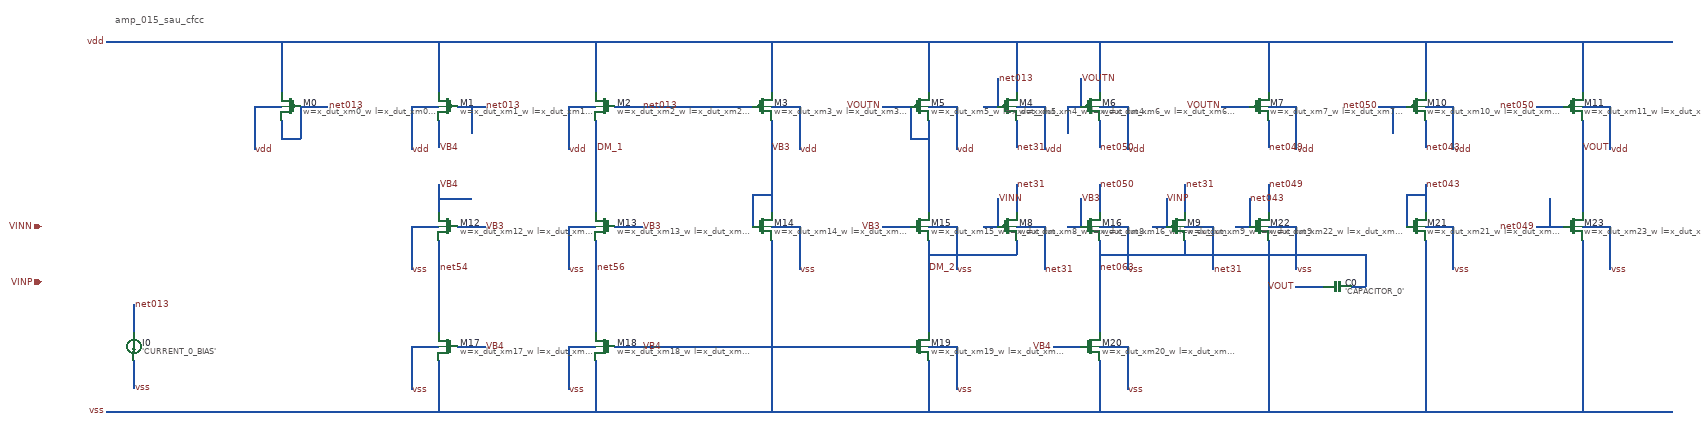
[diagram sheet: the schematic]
v {xschem version=3.4.6 file_version=1.2}
G {}
K {}
V {}
S {}
E {}
T {amp_015_sau_cfcc} -1740 -200 0 0 0.4 0.4 {}
C {devices/capa_np.sym} 905 390 1 0 {name=C0 value='CAPACITOR_0'}
C {devices/isource_np.sym} -1700 520 0 0 {name=I0 value='CURRENT_0_BIAS'}
C {devices/sg13_lv_pmos_np.sym} -1360 0 0 1 {name=M0 model=sg13_lv_pmos spiceprefix=X w=x_dut_xm0_w l=x_dut_xm0_l m=x_dut_xm0_m}
C {devices/sg13_lv_pmos_np.sym} -1020 0 0 1 {name=M1 model=sg13_lv_pmos spiceprefix=X w=x_dut_xm1_w l=x_dut_xm1_l m=x_dut_xm1_m}
C {devices/sg13_lv_pmos_np.sym} 1075 0 0 0 {name=M10 model=sg13_lv_pmos spiceprefix=X w=x_dut_xm10_w l=x_dut_xm10_l m=x_dut_xm10_m}
C {devices/sg13_lv_pmos_np.sym} 1415 0 0 0 {name=M11 model=sg13_lv_pmos spiceprefix=X w=x_dut_xm11_w l=x_dut_xm11_l m=x_dut_xm11_m}
C {devices/sg13_lv_nmos_np.sym} -1020 260 0 1 {name=M12 model=sg13_lv_nmos spiceprefix=X w=x_dut_xm12_w l=x_dut_xm12_l m=x_dut_xm12_m}
C {devices/sg13_lv_nmos_np.sym} -680 260 0 1 {name=M13 model=sg13_lv_nmos spiceprefix=X w=x_dut_xm13_w l=x_dut_xm13_l m=x_dut_xm13_m}
C {devices/sg13_lv_nmos_np.sym} -340 260 0 0 {name=M14 model=sg13_lv_nmos spiceprefix=X w=x_dut_xm14_w l=x_dut_xm14_l m=x_dut_xm14_m}
C {devices/sg13_lv_nmos_np.sym} 0 260 0 0 {name=M15 model=sg13_lv_nmos spiceprefix=X w=x_dut_xm15_w l=x_dut_xm15_l m=x_dut_xm15_m}
C {devices/sg13_lv_nmos_np.sym} 370 260 0 0 {name=M16 model=sg13_lv_nmos spiceprefix=X w=x_dut_xm16_w l=x_dut_xm16_l m=x_dut_xm16_m}
C {devices/sg13_lv_nmos_np.sym} -1020 520 0 1 {name=M17 model=sg13_lv_nmos spiceprefix=X w=x_dut_xm17_w l=x_dut_xm17_l m=x_dut_xm17_m}
C {devices/sg13_lv_nmos_np.sym} -680 520 0 1 {name=M18 model=sg13_lv_nmos spiceprefix=X w=x_dut_xm18_w l=x_dut_xm18_l m=x_dut_xm18_m}
C {devices/sg13_lv_nmos_np.sym} 0 520 0 0 {name=M19 model=sg13_lv_nmos spiceprefix=X w=x_dut_xm19_w l=x_dut_xm19_l m=x_dut_xm19_m}
C {devices/sg13_lv_pmos_np.sym} -680 0 0 1 {name=M2 model=sg13_lv_pmos spiceprefix=X w=x_dut_xm2_w l=x_dut_xm2_l m=x_dut_xm2_m}
C {devices/sg13_lv_nmos_np.sym} 370 520 0 0 {name=M20 model=sg13_lv_nmos spiceprefix=X w=x_dut_xm20_w l=x_dut_xm20_l m=x_dut_xm20_m}
C {devices/sg13_lv_nmos_np.sym} 1075 260 0 0 {name=M21 model=sg13_lv_nmos spiceprefix=X w=x_dut_xm21_w l=x_dut_xm21_l m=x_dut_xm21_m}
C {devices/sg13_lv_nmos_np.sym} 735 260 0 0 {name=M22 model=sg13_lv_nmos spiceprefix=X w=x_dut_xm22_w l=x_dut_xm22_l m=x_dut_xm22_m}
C {devices/sg13_lv_nmos_np.sym} 1415 260 0 0 {name=M23 model=sg13_lv_nmos spiceprefix=X w=x_dut_xm23_w l=x_dut_xm23_l m=x_dut_xm23_m}
C {devices/sg13_lv_pmos_np.sym} -340 0 0 0 {name=M3 model=sg13_lv_pmos spiceprefix=X w=x_dut_xm3_w l=x_dut_xm3_l m=x_dut_xm3_m}
C {devices/sg13_lv_pmos_np.sym} 190 0 0 0 {name=M4 model=sg13_lv_pmos spiceprefix=X w=x_dut_xm4_w l=x_dut_xm4_l m=x_dut_xm4_m}
C {devices/sg13_lv_pmos_np.sym} 0 0 0 0 {name=M5 model=sg13_lv_pmos spiceprefix=X w=x_dut_xm5_w l=x_dut_xm5_l m=x_dut_xm5_m}
C {devices/sg13_lv_pmos_np.sym} 370 0 0 0 {name=M6 model=sg13_lv_pmos spiceprefix=X w=x_dut_xm6_w l=x_dut_xm6_l m=x_dut_xm6_m}
C {devices/sg13_lv_pmos_np.sym} 735 0 0 0 {name=M7 model=sg13_lv_pmos spiceprefix=X w=x_dut_xm7_w l=x_dut_xm7_l m=x_dut_xm7_m}
C {devices/sg13_lv_pmos_np.sym} 190 260 0 0 {name=M8 model=sg13_lv_pmos spiceprefix=X w=x_dut_xm8_w l=x_dut_xm8_l m=x_dut_xm8_m}
C {devices/sg13_lv_pmos_np.sym} 555 260 0 0 {name=M9 model=sg13_lv_pmos spiceprefix=X w=x_dut_xm9_w l=x_dut_xm9_l m=x_dut_xm9_m}
N -1700 430 -1700 490 {}
N -1700 550 -1700 610 {}
N -1440 0 -1440 94 {}
N -1380 -140 -1380 -30 {}
N -1380 30 -1380 70 {}
N -1340 0 -1340 70 {}
N -1100 0 -1100 94 {}
N -1100 260 -1100 354 {}
N -1100 520 -1100 614 {}
N -1040 -140 -1040 -30 {}
N -1040 30 -1040 90 {}
N -1040 170 -1040 230 {}
N -1040 290 -1040 490 {}
N -1040 550 -1040 660 {}
N -970 0 -970 60 {}
N -760 0 -760 94 {}
N -760 260 -760 354 {}
N -760 520 -760 614 {}
N -700 -140 -700 -30 {}
N -700 30 -700 230 {}
N -700 290 -700 490 {}
N -700 550 -700 660 {}
N -360 190 -360 260 {}
N -320 -140 -320 -30 {}
N -320 30 -320 230 {}
N -320 290 -320 660 {}
N -260 0 -260 94 {}
N -260 260 -260 354 {}
N -20 0 -20 70 {}
N 20 -140 20 -30 {}
N 20 30 20 230 {}
N 20 290 20 490 {}
N 20 550 20 660 {}
N 80 0 80 94 {}
N 80 260 80 354 {}
N 80 520 80 614 {}
N 170 -60 170 0 {}
N 170 200 170 260 {}
N 210 -140 210 -30 {}
N 210 30 210 90 {}
N 210 170 210 230 {}
N 210 290 210 320 {}
N 270 0 270 94 {}
N 270 260 270 354 {}
N 320 0 320 60 {}
N 350 -60 350 0 {}
N 350 200 350 260 {}
N 390 -140 390 -30 {}
N 390 30 390 90 {}
N 390 170 390 230 {}
N 390 290 390 490 {}
N 390 550 390 660 {}
N 450 0 450 94 {}
N 450 260 450 354 {}
N 450 520 450 614 {}
N 535 200 535 260 {}
N 575 170 575 230 {}
N 575 290 575 320 {}
N 635 260 635 354 {}
N 715 200 715 260 {}
N 755 -140 755 -30 {}
N 755 30 755 90 {}
N 755 170 755 230 {}
N 755 290 755 660 {}
N 815 0 815 94 {}
N 815 260 815 354 {}
N 965 320 965 390 {}
N 1025 0 1025 60 {}
N 1055 190 1055 260 {}
N 1095 -140 1095 -30 {}
N 1095 30 1095 90 {}
N 1095 170 1095 230 {}
N 1095 290 1095 660 {}
N 1155 0 1155 94 {}
N 1155 260 1155 354 {}
N 1365 200 1365 260 {}
N 1435 -140 1435 -30 {}
N 1435 30 1435 230 {}
N 1435 290 1435 660 {}
N 1495 0 1495 94 {}
N 1495 260 1495 354 {}
N -1760 -140 1630 -140 {}
N -1440 0 -1380 0 {}
N -1340 0 -1280 0 {}
N -1100 0 -1040 0 {}
N -1000 0 -940 0 {}
N -760 0 -700 0 {}
N -660 0 -360 0 {}
N -320 0 -260 0 {}
N -80 0 -20 0 {}
N 20 0 80 0 {}
N 140 0 170 0 {}
N 210 0 270 0 {}
N 320 0 350 0 {}
N 390 0 450 0 {}
N 655 0 715 0 {}
N 755 0 815 0 {}
N 995 0 1055 0 {}
N 1095 0 1155 0 {}
N 1335 0 1395 0 {}
N 1435 0 1495 0 {}
N -1380 70 -1340 70 {}
N -20 70 20 70 {}
N -360 190 -320 190 {}
N 1055 190 1095 190 {}
N -1040 200 -970 200 {}
N -1100 260 -1040 260 {}
N -1000 260 -940 260 {}
N -760 260 -700 260 {}
N -660 260 -600 260 {}
N -320 260 -260 260 {}
N -80 260 -20 260 {}
N 20 260 80 260 {}
N 140 260 170 260 {}
N 210 260 270 260 {}
N 320 260 350 260 {}
N 390 260 450 260 {}
N 505 260 535 260 {}
N 575 260 635 260 {}
N 685 260 715 260 {}
N 755 260 815 260 {}
N 1095 260 1155 260 {}
N 1335 260 1395 260 {}
N 1435 260 1495 260 {}
N 20 320 210 320 {}
N 390 320 965 320 {}
N 815 390 875 390 {}
N 935 390 965 390 {}
N -1100 520 -1040 520 {}
N -1000 520 -940 520 {}
N -760 520 -700 520 {}
N -660 520 -20 520 {}
N 20 520 80 520 {}
N 290 520 350 520 {}
N 390 520 450 520 {}
N -1760 660 1630 660 {}
C {devices/lab_wire.sym} -1760 -140 0 0 {name=l0 lab=vdd}
C {devices/lab_wire.sym} -1760 660 0 0 {name=l1 lab=vss}
C {devices/lab_wire.sym} -700 90 2 0 {name=l2 lab=DM_1}
C {devices/lab_wire.sym} 20 350 2 0 {name=l3 lab=DM_2}
C {devices/lab_wire.sym} -940 260 0 1 {name=l4 lab=VB3}
C {devices/lab_wire.sym} -600 260 0 1 {name=l5 lab=VB3}
C {devices/lab_wire.sym} -320 90 2 0 {name=l6 lab=VB3}
C {devices/lab_wire.sym} -80 260 0 0 {name=l7 lab=VB3}
C {devices/lab_wire.sym} 350 200 0 1 {name=l8 lab=VB3}
C {devices/lab_wire.sym} -1040 90 2 0 {name=l9 lab=VB4}
C {devices/lab_wire.sym} -1040 170 0 1 {name=l10 lab=VB4}
C {devices/lab_wire.sym} -940 520 0 1 {name=l11 lab=VB4}
C {devices/lab_wire.sym} -600 520 0 1 {name=l12 lab=VB4}
C {devices/lab_wire.sym} 290 520 0 0 {name=l13 lab=VB4}
C {devices/lab_wire.sym} 170 200 0 1 {name=l14 lab=VINN}
C {devices/lab_wire.sym} 535 200 0 1 {name=l15 lab=VINP}
C {devices/lab_wire.sym} 815 390 0 0 {name=l16 lab=VOUT}
C {devices/lab_wire.sym} 1435 90 2 0 {name=l17 lab=VOUT}
C {devices/lab_wire.sym} -80 0 0 0 {name=l18 lab=VOUTN}
C {devices/lab_wire.sym} 350 -60 0 1 {name=l19 lab=VOUTN}
C {devices/lab_wire.sym} 655 0 0 0 {name=l20 lab=VOUTN}
C {devices/lab_wire.sym} -1280 0 0 1 {name=l21 lab=net013}
C {devices/lab_wire.sym} -940 0 0 1 {name=l22 lab=net013}
C {devices/lab_wire.sym} -600 0 0 1 {name=l23 lab=net013}
C {devices/lab_wire.sym} 170 -60 0 1 {name=l24 lab=net013}
C {devices/lab_wire.sym} 715 200 0 1 {name=l25 lab=net043}
C {devices/lab_wire.sym} 1095 170 0 1 {name=l26 lab=net043}
C {devices/lab_wire.sym} 1095 90 2 0 {name=l27 lab=net043}
C {devices/lab_wire.sym} 755 90 2 0 {name=l28 lab=net049}
C {devices/lab_wire.sym} 755 170 0 1 {name=l29 lab=net049}
C {devices/lab_wire.sym} 1335 260 0 0 {name=l30 lab=net049}
C {devices/lab_wire.sym} 390 90 2 0 {name=l31 lab=net050}
C {devices/lab_wire.sym} 390 170 0 1 {name=l32 lab=net050}
C {devices/lab_wire.sym} 995 0 0 0 {name=l33 lab=net050}
C {devices/lab_wire.sym} 1335 0 0 0 {name=l34 lab=net050}
C {devices/lab_wire.sym} 390 350 2 0 {name=l35 lab=net063}
C {devices/lab_wire.sym} 210 90 2 0 {name=l36 lab=net31}
C {devices/lab_wire.sym} 210 170 0 1 {name=l37 lab=net31}
C {devices/lab_wire.sym} 575 170 0 1 {name=l38 lab=net31}
C {devices/lab_wire.sym} -1040 350 2 0 {name=l39 lab=net54}
C {devices/lab_wire.sym} -700 350 2 0 {name=l40 lab=net56}
C {devices/lab_wire.sym} 270 354 2 0 {name=l41 lab=net31}
C {devices/lab_wire.sym} 635 354 2 0 {name=l42 lab=net31}
C {devices/lab_wire.sym} -1440 94 2 0 {name=l43 lab=vdd}
C {devices/lab_wire.sym} -1100 94 2 0 {name=l44 lab=vdd}
C {devices/lab_wire.sym} 1155 94 2 0 {name=l45 lab=vdd}
C {devices/lab_wire.sym} 1495 94 2 0 {name=l46 lab=vdd}
C {devices/lab_wire.sym} -760 94 2 0 {name=l47 lab=vdd}
C {devices/lab_wire.sym} -260 94 2 0 {name=l48 lab=vdd}
C {devices/lab_wire.sym} 270 94 2 0 {name=l49 lab=vdd}
C {devices/lab_wire.sym} 80 94 2 0 {name=l50 lab=vdd}
C {devices/lab_wire.sym} 450 94 2 0 {name=l51 lab=vdd}
C {devices/lab_wire.sym} 815 94 2 0 {name=l52 lab=vdd}
C {devices/lab_wire.sym} -1100 354 2 0 {name=l53 lab=vss}
C {devices/lab_wire.sym} -760 354 2 0 {name=l54 lab=vss}
C {devices/lab_wire.sym} -260 354 2 0 {name=l55 lab=vss}
C {devices/lab_wire.sym} 80 354 2 0 {name=l56 lab=vss}
C {devices/lab_wire.sym} 450 354 2 0 {name=l57 lab=vss}
C {devices/lab_wire.sym} -1100 614 2 0 {name=l58 lab=vss}
C {devices/lab_wire.sym} -760 614 2 0 {name=l59 lab=vss}
C {devices/lab_wire.sym} 80 614 2 0 {name=l60 lab=vss}
C {devices/lab_wire.sym} 450 614 2 0 {name=l61 lab=vss}
C {devices/lab_wire.sym} 1155 354 2 0 {name=l62 lab=vss}
C {devices/lab_wire.sym} 815 354 2 0 {name=l63 lab=vss}
C {devices/lab_wire.sym} 1495 354 2 0 {name=l64 lab=vss}
C {devices/lab_wire.sym} -1700 430 0 1 {name=l65 lab=net013}
C {devices/lab_wire.sym} -1700 610 2 0 {name=l66 lab=vss}
C {devices/ipin.sym} -1900 260 0 0 {name=p0 lab=VINN}
C {devices/ipin.sym} -1900 380 0 0 {name=p1 lab=VINP}
